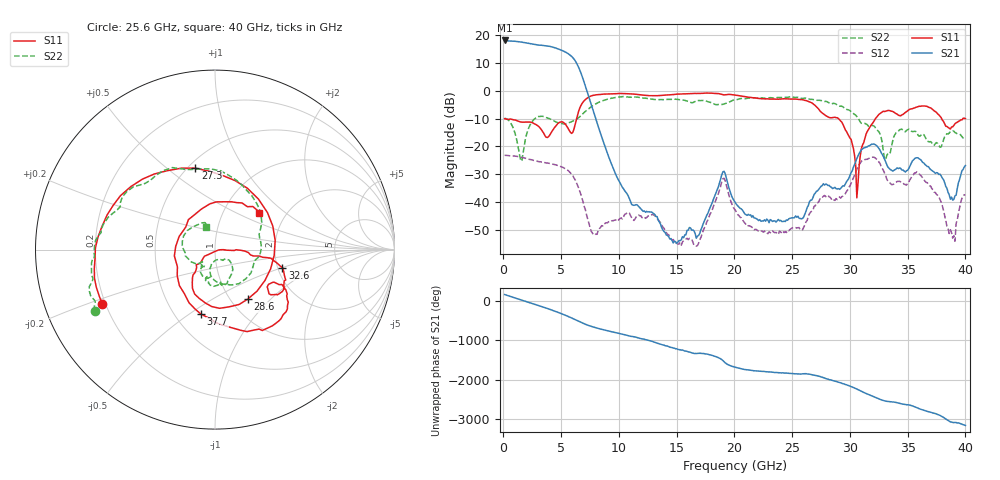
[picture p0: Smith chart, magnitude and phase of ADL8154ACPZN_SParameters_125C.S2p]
! Analog Devices, Inc."
! Device:	ADL8154ACPZN
! Description:	"10 MHz to 6 GHz, Wideband, Low Noise Amplifier"
! Conditions:	Vdd = 5.0 V
!		IDQ = 125 mA
!		Pin = -25 dBm
!		Operating Temperature = +125 C (at package bottom)
! Product validation unit SN30 soldered down to Evaluation Board as shown on ADL8154-EVALZ User Guide. Board loss de-embedded from S21 magnitude.  All other RF measurements reference to RF coaxial connector.
! Frequency (GHz)	S11_Mag (dB)	S11_Phase (deg)	S21_Mag (dB)	S21_Phase (deg)	S12_Mag (dB)	S12_Phase (deg)	S22_Mag (dB)	S22_Phase (deg)
#  GHZ  S  DB  R 50
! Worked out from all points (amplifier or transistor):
!   400 points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, 110 MHz to 40 GHz, reference 50 ohm
!   highest |S21| = 18.0 dB at 110 MHz (marker M1)
!   |S21| within 3 dB of that: start of sweep to 4.718 GHz
!   unconditionally stable (mu >= 1): start of sweep to end of sweep
!   at 6.708 GHz: K = 10.44, MAG = 8.6 dB, |S12| = -37.2 dB
!   at 20.11 GHz: K = 1197.35, MAG = -32.4 dB, |S12| = -43.0 dB
!   at 40 GHz: K = 728.65, MAG = -26.3 dB, |S12| = -37.5 dB
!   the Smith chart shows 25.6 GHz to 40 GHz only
!   S11 on the Smith chart (normalised r, x): 25.6 GHz: 0.19, -0.22; 27.3 GHz: 0.54, +0.63; 28.6 GHz: 1.20, -0.74; 32.6 GHz: 2.12, -0.50; 37.7 GHz: 0.67, -0.56; 40 GHz: 1.47, +0.66
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0.11  -10.04 -178.6  18.02 170.1  -23.16 -6.0  -9.89 168.2
0.91  -10.46 144.5  17.75 93.8  -23.40 -67.6  -13.99 90.9
1.81  -11.29 112.1  17.24 8.2  -24.09 -136.6  -19.55 -118.0
2.709  -11.92 60.6  16.60 -76.4  -25.09 153.9  -10.09 152.3
3.609  -16.15 -48.9  16.14 -164.3  -25.80 82.6  -9.42 90.1
4.009  -15.97 -129.9  15.91 154.3  -26.08 49.2  -10.04 64.8
4.509  -12.81 153.8  15.34 100.7  -26.57 6.4  -11.10 27.8
5.309  -11.76 61.3  14.01 9.3  -27.85 -66.8  -11.89 -53.7
6.009  -14.99 -82.8  11.89 -80.8  -30.40 -140.4  -10.93 -128.4
6.408  -8.89 -177.5  9.34 -137.3  -33.78 172.3  -10.04 -163.1
6.808  -4.64 127.7  5.32 168.0  -38.51 122.6  -8.58 164.6
7.808  -1.63 44.7  -7.54 60.9  -51.69 -24.2  -5.17 81.4
13.407  -1.77 170.5  -46.40 0.4  -46.20 -1.2  -3.20 169.7
20.105  -1.61 10.9  -40.27 113.5  -43.02 113.1  -3.27 -7.5
25.604  -3.14 -154.2  -45.74 -58.0  -49.09 -60.8  -2.46 -153.0
26.803  -4.65 143.1  -38.34 -81.0  -42.92 -79.8  -3.15 -171.5
27.303  -6.62 103.6  -35.37 -109.4  -39.80 -114.3  -3.43 -178.3
28.603  -9.61 -56.5  -34.88 128.4  -39.12 126.8  -4.52 150.3
32.602  -8.20 -14.9  -21.25 18.7  -26.06 19.4  -15.39 -91.5
33.402  -7.09 -31.9  -27.84 -41.6  -32.86 -38.3  -22.72 -51.0
37.701  -8.67 -102.2  -30.04 -19.4  -38.06 -15.4  -19.63 -135.2
40  -10.01 39.7  -26.87 71.5  -37.48 59.4  -17.27 111.4
